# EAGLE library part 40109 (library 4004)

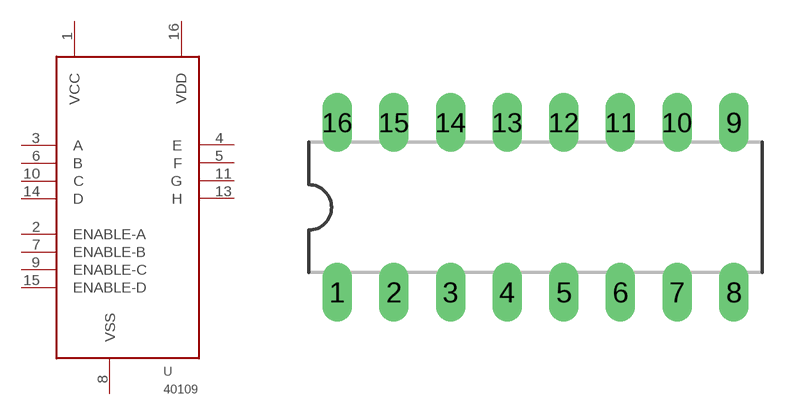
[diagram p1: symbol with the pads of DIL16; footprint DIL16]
Designator prefix -

## 40109  [DIL16]
1  VCC
2  ENABLE-A
3  A
4  E
5  F
6  B
7  ENABLE-B
8  VSS
9  ENABLE-C
10  C
11  G
13  H
14  D
15  ENABLE-D
16  VDD

## Footprint DIL16 (pad centres in mm)
drill 0.813 long: 1 -7.62,-3.81; 2 -5.08,-3.81; 3 -2.54,-3.81; 4 0,-3.81; 5 2.54,-3.81; 6 5.08,-3.81; 7 7.62,-3.81; 8 10.16,-3.81; 9 10.16,3.81; 10 7.62,3.81; 11 5.08,3.81; 12 2.54,3.81; 13 0,3.81; 14 -2.54,3.81; 15 -5.08,3.81; 16 -7.62,3.81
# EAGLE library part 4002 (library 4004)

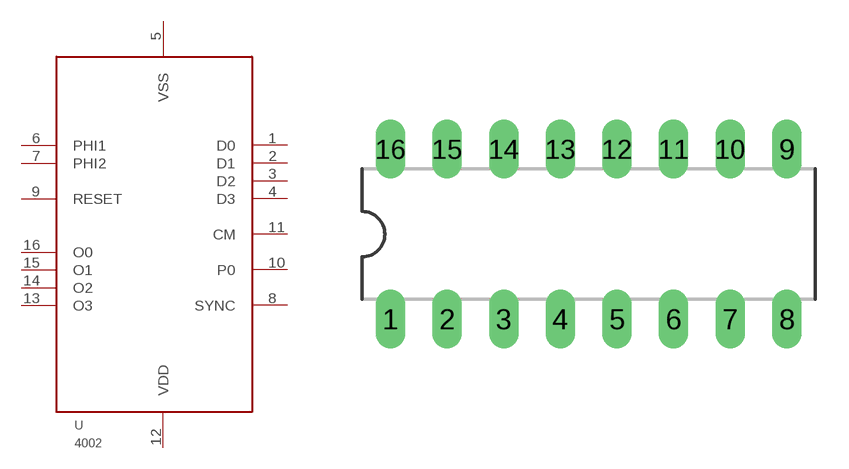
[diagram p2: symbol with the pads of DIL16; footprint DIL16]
Designator prefix -

## 4002  [DIL16]
1  D0
2  D1
3  D2
4  D3
5  VSS
6  PHI1
7  PHI2
8  SYNC
9  RESET
10  P0
11  CM
12  VDD
13  O3
14  O2
15  O1
16  O0

## Footprint DIL16 (pad centres in mm)
drill 0.813 long: 1 -7.62,-3.81; 2 -5.08,-3.81; 3 -2.54,-3.81; 4 0,-3.81; 5 2.54,-3.81; 6 5.08,-3.81; 7 7.62,-3.81; 8 10.16,-3.81; 9 10.16,3.81; 10 7.62,3.81; 11 5.08,3.81; 12 2.54,3.81; 13 0,3.81; 14 -2.54,3.81; 15 -5.08,3.81; 16 -7.62,3.81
